! (c) 2009  Infineon Technologies AG, Munich
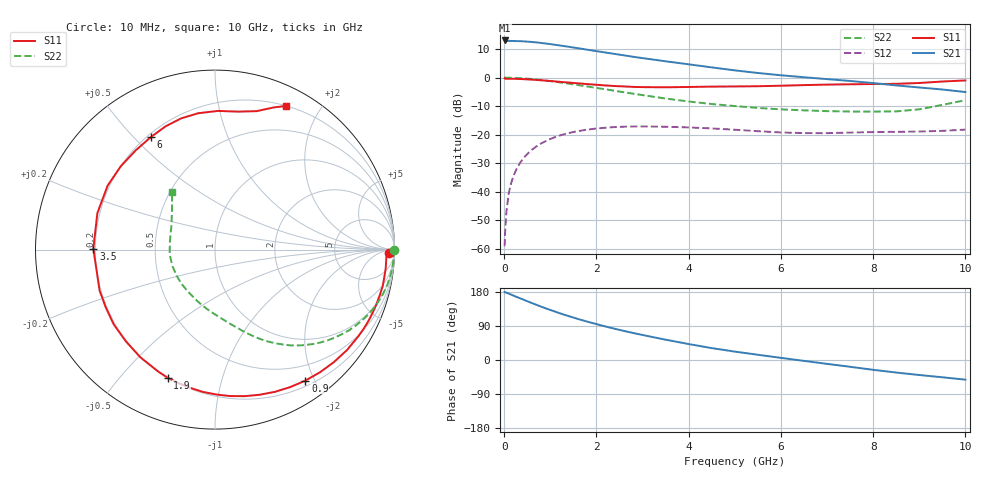
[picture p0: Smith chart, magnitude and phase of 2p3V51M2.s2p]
! Infineon Technologies  Discrete & RF Semiconductors
! BFP420
! VCE =  3.5 V,  IC =  1.2 mA
! Common Emitter S-Parameters:  Nov 2009
# GHz  S  MA  R  50
!  f  S11  S21  S12  S22
! GHz  MAG  ANG  MAG  ANG  MAG  ANG  MAG  ANG
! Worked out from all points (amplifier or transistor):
!   46 points, 10 MHz to 10 GHz, reference 50 ohm
!   highest |S21| = 13.1 dB at 10 MHz (marker M1)
!   |S21| within 3 dB of that: start of sweep to 1.712 GHz
!   unconditionally stable (mu >= 1): 4.283 GHz to end of sweep
!   at 300 MHz: K = 0.03, MSG = 22.0 dB, |S12| = -31.2 dB
!   at 1.7 GHz: K = 0.28, MSG = 14.3 dB, |S12| = -18.5 dB
!   at 10 GHz: K = 1.31, MAG = 3.2 dB, |S12| = -18.2 dB
!   lowest NFmin = 0.53 dB at 900 MHz
!   S11 on the Smith chart (normalised r, x): 10 MHz: 44, -28; 900 MHz: 0.27, -1.87; 1.9 GHz: 0.20, -0.68; 3.5 GHz: 0.19, +0.00; 6 GHz: 0.21, +0.56; 10 GHz: 0.20, +1.59
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0.01  0.9681 -1.2  4.5 179.2  0.0011 94.5  0.9966 0.0
0.02  0.9569 -1.2  4.358 179.3  0.0019 80.8  0.9965 -0.6
0.05  0.9557 -3.0  4.389 177.5  0.0045 86.4  0.9967 -1.6
0.1  0.9568 -6.3  4.414 175.1  0.0094 85.6  0.9962 -3.3
0.2  0.9562 -12.3  4.41 170.1  0.0185 82.5  0.9915 -6.7
0.4  0.9429 -24.9  4.348 160.2  0.0367 75.2  0.9741 -13.2
0.6  0.9242 -37.3  4.232 150.3  0.054 68.0  0.9464 -19.6
0.9  0.8867 -55.4  3.977 136.4  0.0769 57.5  0.8911 -28.4
1.2  0.8461 -72.9  3.683 123.6  0.096 47.9  0.8274 -36.4
1.4  0.8202 -84.2  3.484 115.8  0.1064 41.9  0.7845 -41.2
1.7  0.7828 -100.1  3.198 104.8  0.1189 33.7  0.7207 -47.7
1.9  0.7609 -110.3  3.014 98.0  0.1252 28.6  0.68 -51.7
2.2  0.7301 -124.7  2.761 88.4  0.1323 21.7  0.6233 -57.0
2.6  0.7013 -143.6  2.463 76.6  0.1378 13.1  0.5536 -63.6
3  0.6821 -160.5  2.205 66.0  0.1392 5.7  0.4941 -69.6
3.5  0.6778 179.6  1.938 53.6  0.1375 -2.0  0.4307 -77.2
4.5  0.6963 149.2  1.515 31.4  0.1284 -13.3  0.3447 -94.5
5.5  0.7076 128.7  1.208 13.8  0.1149 -19.2  0.2943 -112.9
6  0.7217 119.7  1.102 5.7  0.1091 -19.7  0.2775 -123.3
7  0.755 104.5  0.943 -10.2  0.1063 -18.5  0.2585 -145.7
8.5  0.7796 80.4  0.731 -33.1  0.1119 -20.1  0.2557 169.2
10  0.8938 63.6  0.559 -51.8  0.1224 -20.4  0.4022 126.5
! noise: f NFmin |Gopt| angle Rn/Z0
0.9  0.53  0.62  33  0.31
1.8  1.1  0.4  77  0.24
2.4  1.23  0.41  100  0.2
3  1.51  0.41  132  0.14
4  1.8  0.44  -175  0.09
5  2.23  0.45  -132  0.38
6  3.18  0.57  -116  0.44
